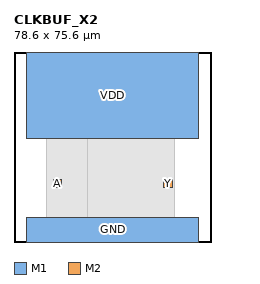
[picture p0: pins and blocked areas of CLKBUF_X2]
MACRO CLKBUF_X2
  CLASS CORE ;
  ORIGIN 0 0 ;
  SIZE 78.600 BY 75.600 ;
  SYMMETRY X Y ;
  SITE TR1um_access_site ;
  PIN VDD
    DIRECTION INOUT ;
    USE POWER ;
    PORT
      LAYER M1 ;
        RECT 5.000 41.000 73.600 75.600 ;
    END
  END VDD
  PIN GND
    DIRECTION INOUT ;
    USE GROUND ;
    PORT
      LAYER M1 ;
        RECT 5.000 0.000 73.600 9.800 ;
    END
  END GND
  PIN A
    DIRECTION INPUT ;
    USE SIGNAL ;
    PORT
      LAYER M2 ;
        RECT 15.600 21.600 19.000 25.000 ;
    END
  END A
  PIN Y
    DIRECTION OUTPUT ;
    USE SIGNAL ;
    PORT
      LAYER M2 ;
        RECT 59.600 21.600 63.000 25.000 ;
    END
  END Y
  OBS
    LAYER M1 ;
      RECT 15.600 16.400 19.700 34.400 ;
    LAYER M1 ;
      RECT 13.100 6.400 57.700 51.200 ;
    LAYER M1 ;
      RECT 29.100 6.400 63.700 51.200 ;
    LAYER V1 ;
      RECT 16.600 22.600 18.000 24.000 ;
    LAYER V1 ;
      RECT 60.600 22.600 62.000 24.000 ;
  END
END CLKBUF_X2
